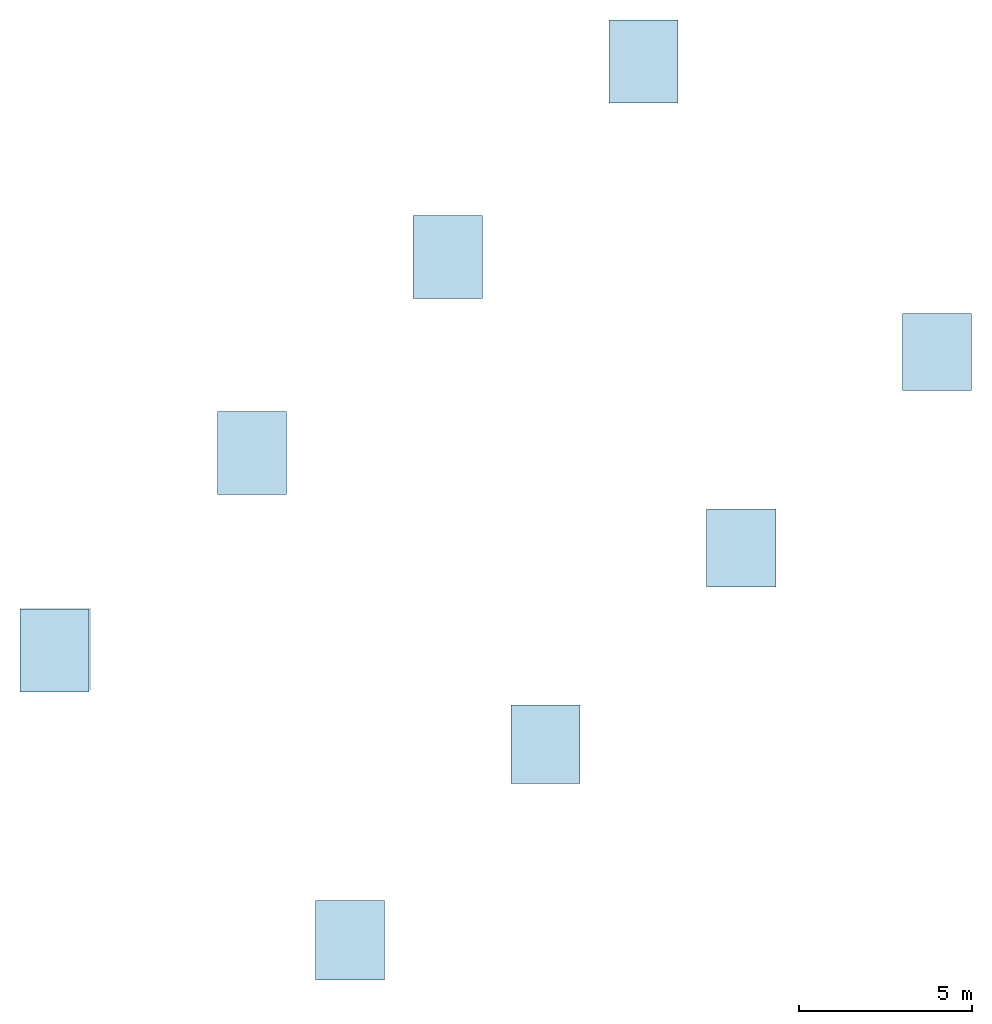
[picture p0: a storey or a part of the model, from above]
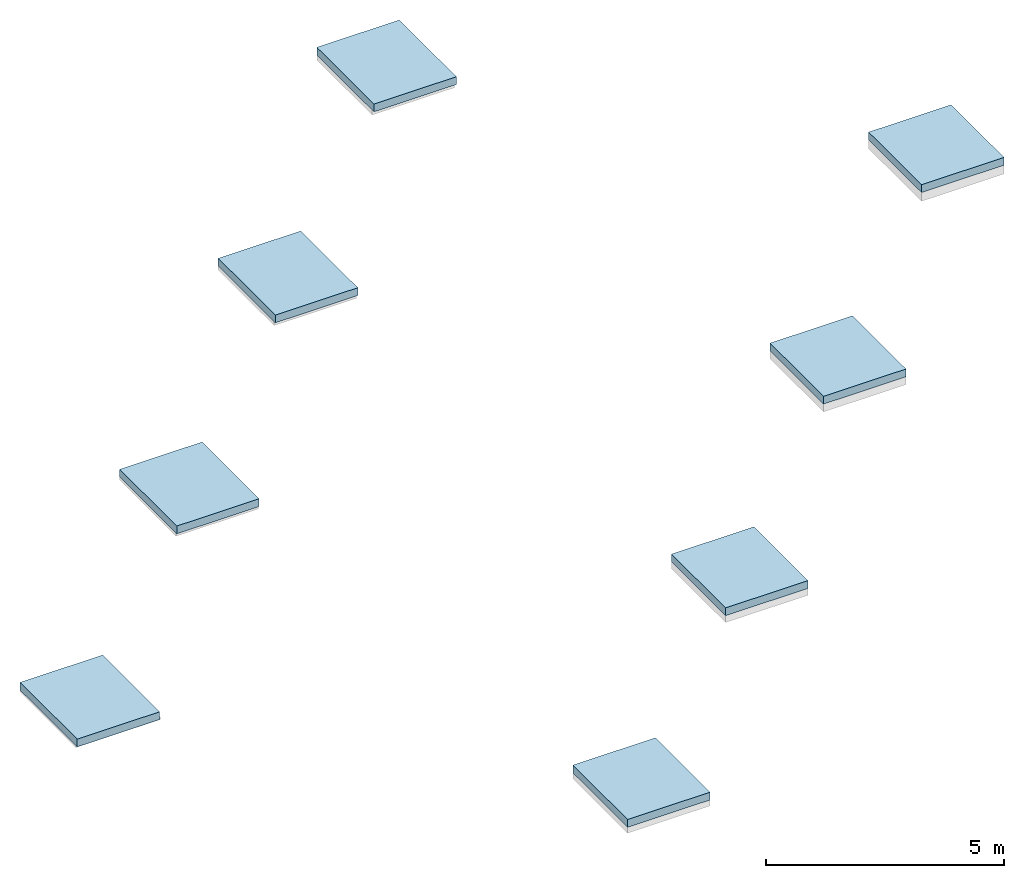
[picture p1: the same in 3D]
Properties of the parts of a building model (IFC2X3), part 1 of 2

# File
Description: ViewDefinition [CoordinationView]
File name: 012345
Time: 2023-01-18T09:48:52
Written by: The EXPRESS Data Manager Version 5.02.0100.07 : 28 Aug 2013
Made in: 21.1.70.21 - Exporter 21.1.70.21 - Alternate UI 21.1.70.21
Comment: STEP Physical File produced by: The EXPRESS Data Manager Version 5.02.0100.07 : 28 Aug 2013 * Module: EDMstepFileFactory/EDMstandAlone * Creation date: Wed Jan 18 09:48:52 2023 * Host: BIM-LT03 * Database: C:\Users\DONNEE~1\AppData\Local\Temp\6dfd9f73-01cb-4fe2-bb7c-203e315a706e\d850b57d-e325-4d6a-91ff-5ca95ef8eb42\ifc * Database version: 5507 * Database creation date: Wed Jan 18 09:48:50 2023 * Schema: IFC2X3 * Model: DataRepository.ifc * Model creation date: Wed Jan 18 09:48:51 2023 * Header model: DataRepository.ifc_HeaderModel * Header model creation date: Wed Jan 18 09:48:51 2023 * EDMuser: sdai-user * EDMgroup: sdai-group * License ID and type: 5605 : Permanent license. Expiry date: * EDMstepFileFactory options: 020000

# IfcProject, 012345
LongName: Cadix Project Naam; Phase: Cadix leeg V2.0

# IfcSite, Default
RefLatitude: 52, 3, 20, 225830; RefLongitude: 5, 6, 28, 692855; RefElevation: 0 mm
Pset_ProductRequirements - Category: Project Information

# IfcBuilding
Pset_BuildingCommon - NumberOfStoreys: 2
Pset_ProductRequirements - Category: Project Information

# IfcBuildingStorey: Level:niveau (2)
Pset_ProductRequirements - Category: Levels
Name | LongName = Pset_AirSideSystemInformation, Name = Pset_ProductRequirements, Name | Elevation (mm)
00 begane grond | 00 begane grond | -2.7707e-11
01 eerste verdieping | 01 eerste verdieping | 1000

# IfcCovering: Compound Ceiling:NLRS_45_CEI_Heraklith Tektalan A2 SmartTec 100x1000x600mm, Compound Ceiling:NLRS_45_CEI_Heraklith Tektalan A2 SmartTec 100x1000x600mm:929619
In: 01 eerste verdieping
Type - PredefinedType: CEILING
Type - Pset_CoveringCommon - Reference: Compound Ceiling:NLRS_45_CEI_Heraklith Tektalan A2 SmartTec 100x1000x600mm; TotalThickness: 100 mm
Type - Pset_ElementShading - Roughness: 304.8 mm
Type - Pset_ManufacturerTypeInformation - Manufacturer: Knauf Insulation B.V.
Type - Pset_ProductRequirements - Category: Ceilings
Type - Pset_QuantityTakeOff - Reference: Compound Ceiling:NLRS_45_CEI_Heraklith Tektalan A2 SmartTec 100x1000x600mm
Type - Pset_Ceiling Schedule LOD200 - Assembly Code: 45.0; Type Image: Raster image: Heraklith Tektalan A2.jpg; Model: Heraklith® | Tektalan A2 SmartTec is een A2 houtwolcementpaneel gecombineerd met een steenwol-plaat.; Manufacturer: Knauf Insulation B.V.; URL: www.heraklith.nl; Description: Tektalan A2 SmartTec - 100mm; phone: +31(0)162-421245; email: customerservice.nl@knaufinsulation.com; product URL: https://heraklith.nl/houtwol-producten/tektalan-a2-smarttec; warmteweerstand: 2,75 (m2.K/W); NLRS_C_Code_Brandklasse: A2-s1,d0; brandweerstand: REI 120/180 mits verwerkt tegen massief beton conform classificatierapport nr 18203 / 18204; geluidsabsorbtie: 1,00; DoP: W4302GPCPR; NLRS_C_content_creator: Knauf Insulation; NLRS_C_content_versie: V1.0
Classification: 45.0 (Uniformat); Material: Heraklith® I Tektalan A2 - Steenwol 90 mm, Heraklith® I Tektalan A2 - Houtwollaag - 1000x600mm 10 mm
Pset_CoveringCommon - Finish: Heraklith® I Tektalan A2 - Houtwollaag - 1000x600mm;
Pset_Ceiling Schedule LOD200 - Type: Compound Ceiling: NLRS_45_CEI_Heraklith Tektalan A2 SmartTec 100x1000x600mm

# IfcCovering: Compound Ceiling:NLRS_45_CEI_Heraklith Tektalan A2 SmartTec 125x1000x600mm, Compound Ceiling:NLRS_45_CEI_Heraklith Tektalan A2 SmartTec 125x1000x600mm:929719
In: 01 eerste verdieping
Type - PredefinedType: CEILING
Type - Pset_CoveringCommon - Reference: Compound Ceiling:NLRS_45_CEI_Heraklith Tektalan A2 SmartTec 125x1000x600mm; TotalThickness: 125 mm
Type - Pset_ElementShading - Roughness: 304.8 mm
Type - Pset_ManufacturerTypeInformation - Manufacturer: Knauf Insulation B.V.
Type - Pset_ProductRequirements - Category: Ceilings
Type - Pset_QuantityTakeOff - Reference: Compound Ceiling:NLRS_45_CEI_Heraklith Tektalan A2 SmartTec 125x1000x600mm
Type - Pset_Ceiling Schedule LOD200 - Assembly Code: 45.0; Type Image: Raster image: Heraklith Tektalan A2.jpg; Model: Heraklith® | Tektalan A2 SmartTec is een A2 houtwolcementpaneel gecombineerd met een steenwol-plaat.; Manufacturer: Knauf Insulation B.V.; URL: www.heraklith.nl; Description: Tektalan A2 SmartTec - 125mm; phone: +31(0)162-421245; email: customerservice.nl@knaufinsulation.com; product URL: https://heraklith.nl/houtwol-producten/tektalan-a2-smarttec; warmteweerstand: 3,50 (m2.K/W); NLRS_C_Code_Brandklasse: A2-s1,d0; brandweerstand: REI 120/180 mits verwerkt tegen massief beton conform classificatierapport nr 18203 / 18204; geluidsabsorbtie: 1,00; DoP: W4302GPCPR; NLRS_C_content_creator: Knauf Insulation; NLRS_C_content_versie: V1.0
Classification: 45.0 (Uniformat); Material: Heraklith® I Tektalan A2 - Steenwol 115 mm, Heraklith® I Tektalan A2 - Houtwollaag - 1000x600mm 10 mm
Pset_CoveringCommon - Finish: Heraklith® I Tektalan A2 - Houtwollaag - 1000x600mm;
Pset_Ceiling Schedule LOD200 - Type: Compound Ceiling: NLRS_45_CEI_Heraklith Tektalan A2 SmartTec 125x1000x600mm

# IfcCovering: Compound Ceiling:NLRS_45_CEI_Heraklith Tektalan A2 SmartTec 150x1000x600mm, Compound Ceiling:NLRS_45_CEI_Heraklith Tektalan A2 SmartTec 150x1000x600mm:929827
In: 01 eerste verdieping
Type - PredefinedType: CEILING
Type - Pset_CoveringCommon - Reference: Compound Ceiling:NLRS_45_CEI_Heraklith Tektalan A2 SmartTec 150x1000x600mm; TotalThickness: 150 mm
Type - Pset_ElementShading - Roughness: 304.8 mm
Type - Pset_ManufacturerTypeInformation - Manufacturer: Knauf Insulation B.V.
Type - Pset_ProductRequirements - Category: Ceilings
Type - Pset_QuantityTakeOff - Reference: Compound Ceiling:NLRS_45_CEI_Heraklith Tektalan A2 SmartTec 150x1000x600mm
Type - Pset_Ceiling Schedule LOD200 - Assembly Code: 45.0; Type Image: Raster image: Heraklith Tektalan A2.jpg; Model: Heraklith® | Tektalan A2 SmartTec is een A2 houtwolcementpaneel gecombineerd met een steenwol-plaat.; Manufacturer: Knauf Insulation B.V.; URL: www.heraklith.nl; Description: Tektalan A2 SmartTec - 150mm; phone: +31(0)162-421245; email: customerservice.nl@knaufinsulation.com; product URL: https://heraklith.nl/houtwol-producten/tektalan-a2-smarttec; warmteweerstand: 4,20 (m2.K/W); NLRS_C_Code_Brandklasse: A2-s1,d0; brandweerstand: REI 120/180 mits verwerkt tegen massief beton conform classificatierapport nr 18203 / 18204; geluidsabsorbtie: 1,00; DoP: W4302GPCPR; NLRS_C_content_creator: Knauf Insulation; NLRS_C_content_versie: V1.0
Classification: 45.0 (Uniformat); Material: Heraklith® I Tektalan A2 - Steenwol 140 mm, Heraklith® I Tektalan A2 - Houtwollaag - 1000x600mm 10 mm
Pset_CoveringCommon - Finish: Heraklith® I Tektalan A2 - Houtwollaag - 1000x600mm;
Pset_Ceiling Schedule LOD200 - Type: Compound Ceiling: NLRS_45_CEI_Heraklith Tektalan A2 SmartTec 150x1000x600mm

# IfcCovering: Compound Ceiling:NLRS_45_CEI_Heraklith Tektalan A2 SmartTec 175x1000x600mm, Compound Ceiling:NLRS_45_CEI_Heraklith Tektalan A2 SmartTec 175x1000x600mm:929851
In: 01 eerste verdieping
Type - PredefinedType: CEILING
Type - Pset_CoveringCommon - Reference: Compound Ceiling:NLRS_45_CEI_Heraklith Tektalan A2 SmartTec 175x1000x600mm; TotalThickness: 175 mm
Type - Pset_ElementShading - Roughness: 304.8 mm
Type - Pset_ManufacturerTypeInformation - Manufacturer: Knauf Insulation B.V.
Type - Pset_ProductRequirements - Category: Ceilings
Type - Pset_QuantityTakeOff - Reference: Compound Ceiling:NLRS_45_CEI_Heraklith Tektalan A2 SmartTec 175x1000x600mm
Type - Pset_Ceiling Schedule LOD200 - Assembly Code: 45.0; Type Image: Raster image: Heraklith Tektalan A2.jpg; Model: Heraklith® | Tektalan A2 SmartTec is een A2 houtwolcementpaneel gecombineerd met een steenwol-plaat.; Manufacturer: Knauf Insulation B.V.; URL: www.heraklith.nl; Description: Tektalan A2 SmartTec - 175mm; phone: +31(0)162-421245; email: customerservice.nl@knaufinsulation.com; product URL: https://heraklith.nl/houtwol-producten/tektalan-a2-smarttec; warmteweerstand: 4,95 (m2.K/W); NLRS_C_Code_Brandklasse: A2-s1,d0; brandweerstand: REI 120/180 mits verwerkt tegen massief beton conform classificatierapport nr 18203 / 18204; geluidsabsorbtie: 1,00; DoP: W4302GPCPR; NLRS_C_content_creator: Knauf Insulation; NLRS_C_content_versie: V1.0
Classification: 45.0 (Uniformat); Material: Heraklith® I Tektalan A2 - Steenwol 165 mm, Heraklith® I Tektalan A2 - Houtwollaag - 1000x600mm 10 mm
Pset_CoveringCommon - Finish: Heraklith® I Tektalan A2 - Houtwollaag - 1000x600mm;
Pset_Ceiling Schedule LOD200 - Type: Compound Ceiling: NLRS_45_CEI_Heraklith Tektalan A2 SmartTec 175x1000x600mm

# IfcCovering: Compound Ceiling:NLRS_45_CEI_Heraklith Tektalan A2 SmartTec 200x1000x600mm, Compound Ceiling:NLRS_45_CEI_Heraklith Tektalan A2 SmartTec 200x1000x600mm:929876
In: 01 eerste verdieping
Type - PredefinedType: CEILING
Type - Pset_CoveringCommon - Reference: Compound Ceiling:NLRS_45_CEI_Heraklith Tektalan A2 SmartTec 200x1000x600mm; TotalThickness: 200 mm
Type - Pset_ElementShading - Roughness: 304.8 mm
Type - Pset_ManufacturerTypeInformation - Manufacturer: Knauf Insulation B.V.
Type - Pset_ProductRequirements - Category: Ceilings
Type - Pset_QuantityTakeOff - Reference: Compound Ceiling:NLRS_45_CEI_Heraklith Tektalan A2 SmartTec 200x1000x600mm
Type - Pset_Ceiling Schedule LOD200 - Assembly Code: 45.0; Type Image: Raster image: Heraklith Tektalan A2.jpg; Model: Heraklith® | Tektalan A2 SmartTec is een A2 houtwolcementpaneel gecombineerd met een steenwol-plaat.; Manufacturer: Knauf Insulation B.V.; URL: www.heraklith.nl; Description: Tektalan A2 SmartTec - 200mm; phone: +31(0)162-421245; email: customerservice.nl@knaufinsulation.com; product URL: https://heraklith.nl/houtwol-producten/tektalan-a2-smarttec; warmteweerstand: 5,70 (m2.K/W); NLRS_C_Code_Brandklasse: A2-s1,d0; brandweerstand: REI 120/180 mits verwerkt tegen massief beton conform classificatierapport nr 18203 / 18204; geluidsabsorbtie: 0,95; DoP: W4302GPCPR; NLRS_C_content_creator: Knauf Insulation; NLRS_C_content_versie: V1.0
Classification: 45.0 (Uniformat); Material: Heraklith® I Tektalan A2 - Steenwol 190 mm, Heraklith® I Tektalan A2 - Houtwollaag - 1000x600mm 10 mm
Pset_CoveringCommon - Finish: Heraklith® I Tektalan A2 - Houtwollaag - 1000x600mm;
Pset_Ceiling Schedule LOD200 - Type: Compound Ceiling: NLRS_45_CEI_Heraklith Tektalan A2 SmartTec 200x1000x600mm

# IfcCovering: Compound Ceiling:NLRS_45_CEI_Heraklith Tektalan A2 SmartTec 225x1000x600mm, Compound Ceiling:NLRS_45_CEI_Heraklith Tektalan A2 SmartTec 225x1000x600mm:929901
In: 01 eerste verdieping
Type - PredefinedType: CEILING
Type - Pset_CoveringCommon - Reference: Compound Ceiling:NLRS_45_CEI_Heraklith Tektalan A2 SmartTec 225x1000x600mm; TotalThickness: 225 mm
Type - Pset_ElementShading - Roughness: 304.8 mm
Type - Pset_ManufacturerTypeInformation - Manufacturer: Knauf Insulation B.V.
Type - Pset_ProductRequirements - Category: Ceilings
Type - Pset_QuantityTakeOff - Reference: Compound Ceiling:NLRS_45_CEI_Heraklith Tektalan A2 SmartTec 225x1000x600mm
Type - Pset_Ceiling Schedule LOD200 - Assembly Code: 45.0; Type Image: Raster image: Heraklith Tektalan A2.jpg; Model: Heraklith® | Tektalan A2 SmartTec is een A2 houtwolcementpaneel gecombineerd met een steenwol-plaat.; Manufacturer: Knauf Insulation B.V.; URL: www.heraklith.nl; Description: Tektalan A2 SmartTec - 225mm; phone: +31(0)162-421245; email: customerservice.nl@knaufinsulation.com; product URL: https://heraklith.nl/houtwol-producten/tektalan-a2-smarttec; warmteweerstand: 6,40 (m2.K/W); NLRS_C_Code_Brandklasse: A2-s1,d0; brandweerstand: REI 120/180 mits verwerkt tegen massief beton conform classificatierapport nr 18203 / 18204; geluidsabsorbtie: 0,95; DoP: W4302GPCPR; NLRS_C_content_creator: Knauf Insulation; NLRS_C_content_versie: V1.0
Classification: 45.0 (Uniformat); Material: Heraklith® I Tektalan A2 - Steenwol 215 mm, Heraklith® I Tektalan A2 - Houtwollaag - 1000x600mm 10 mm
Pset_CoveringCommon - Finish: Heraklith® I Tektalan A2 - Houtwollaag - 1000x600mm;
Pset_Ceiling Schedule LOD200 - Type: Compound Ceiling: NLRS_45_CEI_Heraklith Tektalan A2 SmartTec 225x1000x600mm

# IfcCovering: Compound Ceiling:NLRS_45_CEI_Heraklith Tektalan A2 SmartTec 50x1000x600mm, Compound Ceiling:NLRS_45_CEI_Heraklith Tektalan A2 SmartTec 50x1000x600mm:905808
In: 01 eerste verdieping
Type - PredefinedType: CEILING
Type - Pset_CoveringCommon - Reference: Compound Ceiling:NLRS_45_CEI_Heraklith Tektalan A2 SmartTec 50x1000x600mm; TotalThickness: 50 mm
Type - Pset_ElementShading - Roughness: 304.8 mm
Type - Pset_ManufacturerTypeInformation - Manufacturer: Knauf Insulation B.V.
Type - Pset_ProductRequirements - Category: Ceilings
Type - Pset_QuantityTakeOff - Reference: Compound Ceiling:NLRS_45_CEI_Heraklith Tektalan A2 SmartTec 50x1000x600mm
Type - Pset_Ceiling Schedule LOD200 - Assembly Code: 45.0; Type Image: Raster image: Heraklith Tektalan A2.jpg; Model: Heraklith® | Tektalan A2 SmartTec is een A2 houtwolcementpaneel gecombineerd met een steenwol-plaat.; Manufacturer: Knauf Insulation B.V.; URL: www.heraklith.nl; Description: Tektalan A2 SmartTec - 50mm; phone: +31(0)162-421245; email: customerservice.nl@knaufinsulation.com; product URL: https://heraklith.nl/houtwol-producten/tektalan-a2-smarttec; warmteweerstand: 1,25 (m2.K/W); NLRS_C_Code_Brandklasse: A2-s1,d0; brandweerstand: REI 120/180 mits verwerkt tegen massief beton conform classificatierapport nr 18203 / 18204; geluidsabsorbtie: 0,95; DoP: W4302GPCPR; NLRS_C_content_creator: Knauf Insulation; NLRS_C_content_versie: V1.0
Classification: 45.0 (Uniformat); Material: Heraklith® I Tektalan A2 - Steenwol 40 mm, Heraklith® I Tektalan A2 - Houtwollaag - 1000x600mm 10 mm
Pset_CoveringCommon - Finish: Heraklith® I Tektalan A2 - Houtwollaag - 1000x600mm;
Pset_Ceiling Schedule LOD200 - Type: Compound Ceiling: NLRS_45_CEI_Heraklith Tektalan A2 SmartTec 50x1000x600mm

# IfcCovering: Compound Ceiling:NLRS_45_CEI_Heraklith Tektalan A2 SmartTec 75x1000x600mm, Compound Ceiling:NLRS_45_CEI_Heraklith Tektalan A2 SmartTec 75x1000x600mm:929506
In: 01 eerste verdieping
Type - PredefinedType: CEILING
Type - Pset_CoveringCommon - Reference: Compound Ceiling:NLRS_45_CEI_Heraklith Tektalan A2 SmartTec 75x1000x600mm; TotalThickness: 75 mm
Type - Pset_ElementShading - Roughness: 304.8 mm
Type - Pset_ManufacturerTypeInformation - Manufacturer: Knauf Insulation B.V.
Type - Pset_ProductRequirements - Category: Ceilings
Type - Pset_QuantityTakeOff - Reference: Compound Ceiling:NLRS_45_CEI_Heraklith Tektalan A2 SmartTec 75x1000x600mm
Type - Pset_Ceiling Schedule LOD200 - Assembly Code: 45.0; Type Image: Raster image: Heraklith Tektalan A2.jpg; Model: Heraklith® | Tektalan A2 SmartTec is een A2 houtwolcementpaneel gecombineerd met een steenwol-plaat.; Manufacturer: Knauf Insulation B.V.; URL: www.heraklith.nl; Description: Tektalan A2 SmartTec - 75mm; phone: +31(0)162-421245; email: customerservice.nl@knaufinsulation.com; product URL: https://heraklith.nl/houtwol-producten/tektalan-a2-smarttec; warmteweerstand: 2,00 (m2.K/W); NLRS_C_Code_Brandklasse: A2-s1,d0; brandweerstand: REI 120/180 mits verwerkt tegen massief beton conform classificatierapport nr 18203 / 18204; geluidsabsorbtie: 0,95; DoP: W4302GPCPR; NLRS_C_content_creator: Knauf Insulation; NLRS_C_content_versie: V1.0
Classification: 45.0 (Uniformat); Material: Heraklith® I Tektalan A2 - Steenwol 65 mm, Heraklith® I Tektalan A2 - Houtwollaag - 1000x600mm 10 mm
Pset_CoveringCommon - Finish: Heraklith® I Tektalan A2 - Houtwollaag - 1000x600mm;
Pset_Ceiling Schedule LOD200 - Type: Compound Ceiling: NLRS_45_CEI_Heraklith Tektalan A2 SmartTec 75x1000x600mm

# IfcSlab: Floor:Generic 200mm (16)
Type - PredefinedType: FLOOR; Material: Concrete, Precast Panels 200 mm
Type - Pset_ElementShading - Roughness: 914.4 mm
Type - Pset_ProductRequirements - Category: Floors
Type - Pset_QuantityTakeOff - Reference: Floor:Generic 200mm
Type - Pset_ReinforcementBarPitchOfSlab - Reference: Floor:Generic 200mm
Type - Pset_SlabCommon - IsExternal: no; Reference: Floor:Generic 200mm; ThermalTransmittance: 5.23 kg/K/s3
Pset_QuantityTakeOff - sets with these values: 2
Pset_SlabCommon - LoadBearing: no; PitchAngle: 0 deg
Name (Floor:Generic 200mm:...) | In
934649 | 01 eerste verdieping
934796 | 01 eerste verdieping
934810 | 01 eerste verdieping
934824 | 01 eerste verdieping
934838 | 01 eerste verdieping
934854 | 01 eerste verdieping
934868 | 01 eerste verdieping
934884 | 01 eerste verdieping
936492 | 00 begane grond
936538 | 00 begane grond
936553 | 00 begane grond
936570 | 00 begane grond
936585 | 00 begane grond
936600 | 00 begane grond
936619 | 00 begane grond
936634 | 00 begane grond

# IfcSlab: Floor:NLRS_23_FL_Heraklith Tektalan A2 SmartTec 100x1000x600mm, Floor:NLRS_23_FL_Heraklith Tektalan A2 SmartTec 100x1000x600mm:929624
In: 00 begane grond
Type - PredefinedType: FLOOR; Material: Heraklith® I Tektalan A2 - Steenwol 90 mm, Heraklith® I Tektalan A2 - Houtwollaag - 1000x600mm 10 mm
Type - Pset_ElementShading - Roughness: 304.8 mm
Type - Pset_ManufacturerTypeInformation - Manufacturer: Knauf Insulation B.V.
Type - Pset_ProductRequirements - Category: Floors
Type - Pset_QuantityTakeOff - Reference: Floor:NLRS_23_FL_Heraklith Tektalan A2 SmartTec 100x1000x600mm
Type - Pset_ReinforcementBarPitchOfSlab - Description: Tektalan A2 SmartTec - 100mm; Reference: Floor:NLRS_23_FL_Heraklith Tektalan A2 SmartTec 100x1000x600mm
Type - Pset_SlabCommon - IsExternal: no; Reference: Floor:NLRS_23_FL_Heraklith Tektalan A2 SmartTec 100x1000x600mm; ThermalTransmittance: 0.361702 kg/K/s3
Type - Pset_Floor Schedule LOD200 - Assembly Code: 23.0; Type Image: Raster image: Heraklith Tektalan A2.jpg; Model: Heraklith® | Tektalan A2 SmartTec is een A2 houtwolcementpaneel gecombineerd met een steenwol-plaat.; Manufacturer: Knauf Insulation B.V.; URL: www.heraklith.nl; Description: Tektalan A2 SmartTec - 100mm; phone: +31(0)162-421245; email: customerservice.nl@knaufinsulation.com; product URL: https://heraklith.nl/houtwol-producten/tektalan-a2-smarttec; warmteweerstand: 2,75 (m2.K/W); NLRS_C_Code_Brandklasse: A2-s1,d0; brandweerstand: REI 120/180 mits verwerkt tegen massief beton conform classificatierapport nr 18203 / 18204; geluidsabsorbtie: 1,00; DoP: W4302GPCPR; NLRS_C_content_creator: Knauf Insulation; NLRS_C_content_versie: V1.0
Classification: 23.0 (Uniformat)
Pset_SlabCommon - IsExternal: yes; LoadBearing: no; PitchAngle: 0 deg
Pset_Floor Schedule LOD200 - Type: Floor: NLRS_23_FL_Heraklith Tektalan A2 SmartTec 100x1000x600mm

# IfcSlab: Floor:NLRS_23_FL_Heraklith Tektalan A2 SmartTec 125x1000x600mm, Floor:NLRS_23_FL_Heraklith Tektalan A2 SmartTec 125x1000x600mm:929724
In: 00 begane grond
Type - PredefinedType: FLOOR; Material: Heraklith® I Tektalan A2 - Steenwol 115 mm, Heraklith® I Tektalan A2 - Houtwollaag - 1000x600mm 10 mm
Type - Pset_ElementShading - Roughness: 304.8 mm
Type - Pset_ManufacturerTypeInformation - Manufacturer: Knauf Insulation B.V.
Type - Pset_ProductRequirements - Category: Floors
Type - Pset_QuantityTakeOff - Reference: Floor:NLRS_23_FL_Heraklith Tektalan A2 SmartTec 125x1000x600mm
Type - Pset_ReinforcementBarPitchOfSlab - Description: Tektalan A2 SmartTec - 125mm; Reference: Floor:NLRS_23_FL_Heraklith Tektalan A2 SmartTec 125x1000x600mm
Type - Pset_SlabCommon - IsExternal: no; Reference: Floor:NLRS_23_FL_Heraklith Tektalan A2 SmartTec 125x1000x600mm; ThermalTransmittance: 0.285714 kg/K/s3
Type - Pset_Floor Schedule LOD200 - Assembly Code: 23.0; Type Image: Raster image: Heraklith Tektalan A2.jpg; Model: Heraklith® | Tektalan A2 SmartTec is een A2 houtwolcementpaneel gecombineerd met een steenwol-plaat.; Manufacturer: Knauf Insulation B.V.; URL: www.heraklith.nl; Description: Tektalan A2 SmartTec - 125mm; phone: +31(0)162-421245; email: customerservice.nl@knaufinsulation.com; product URL: https://heraklith.nl/houtwol-producten/tektalan-a2-smarttec; warmteweerstand: 3,50 (m2.K/W); NLRS_C_Code_Brandklasse: A2-s1,d0; brandweerstand: REI 120/180 mits verwerkt tegen massief beton conform classificatierapport nr 18203 / 18204; geluidsabsorbtie: 1,00; DoP: W4302GPCPR; NLRS_C_content_creator: Knauf Insulation; NLRS_C_content_versie: V1.0
Classification: 23.0 (Uniformat)
Pset_SlabCommon - IsExternal: yes; LoadBearing: no; PitchAngle: 0 deg
Pset_Floor Schedule LOD200 - Type: Floor: NLRS_23_FL_Heraklith Tektalan A2 SmartTec 125x1000x600mm

# IfcSlab: Floor:NLRS_23_FL_Heraklith Tektalan A2 SmartTec 150x1000x600mm, Floor:NLRS_23_FL_Heraklith Tektalan A2 SmartTec 150x1000x600mm:929832
In: 00 begane grond
Type - PredefinedType: FLOOR; Material: Heraklith® I Tektalan A2 - Steenwol 140 mm, Heraklith® I Tektalan A2 - Houtwollaag - 1000x600mm 10 mm
Type - Pset_ElementShading - Roughness: 304.8 mm
Type - Pset_ManufacturerTypeInformation - Manufacturer: Knauf Insulation B.V.
Type - Pset_ProductRequirements - Category: Floors
Type - Pset_QuantityTakeOff - Reference: Floor:NLRS_23_FL_Heraklith Tektalan A2 SmartTec 150x1000x600mm
Type - Pset_ReinforcementBarPitchOfSlab - Description: Tektalan A2 SmartTec - 150mm; Reference: Floor:NLRS_23_FL_Heraklith Tektalan A2 SmartTec 150x1000x600mm
Type - Pset_SlabCommon - IsExternal: no; Reference: Floor:NLRS_23_FL_Heraklith Tektalan A2 SmartTec 150x1000x600mm; ThermalTransmittance: 0.236111 kg/K/s3
Type - Pset_Floor Schedule LOD200 - Assembly Code: 23.0; Type Image: Raster image: Heraklith Tektalan A2.jpg; Model: Heraklith® | Tektalan A2 SmartTec is een A2 houtwolcementpaneel gecombineerd met een steenwol-plaat.; Manufacturer: Knauf Insulation B.V.; URL: www.heraklith.nl; Description: Tektalan A2 SmartTec - 150mm; phone: +31(0)162-421245; email: customerservice.nl@knaufinsulation.com; product URL: https://heraklith.nl/houtwol-producten/tektalan-a2-smarttec; warmteweerstand: 4,20 (m2.K/W); NLRS_C_Code_Brandklasse: A2-s1,d0; brandweerstand: REI 120/180 mits verwerkt tegen massief beton conform classificatierapport nr 18203 / 18204; geluidsabsorbtie: 1,00; DoP: W4302GPCPR; NLRS_C_content_creator: Knauf Insulation; NLRS_C_content_versie: V1.0
Classification: 23.0 (Uniformat)
Pset_SlabCommon - IsExternal: yes; LoadBearing: no; PitchAngle: 0 deg
Pset_Floor Schedule LOD200 - Type: Floor: NLRS_23_FL_Heraklith Tektalan A2 SmartTec 150x1000x600mm

# IfcSlab: Floor:NLRS_23_FL_Heraklith Tektalan A2 SmartTec 175x1000x600mm, Floor:NLRS_23_FL_Heraklith Tektalan A2 SmartTec 175x1000x600mm:929856
In: 00 begane grond
Type - PredefinedType: FLOOR; Material: Heraklith® I Tektalan A2 - Steenwol 165 mm, Heraklith® I Tektalan A2 - Houtwollaag - 1000x600mm 10 mm
Type - Pset_ElementShading - Roughness: 304.8 mm
Type - Pset_ManufacturerTypeInformation - Manufacturer: Knauf Insulation B.V.
Type - Pset_ProductRequirements - Category: Floors
Type - Pset_QuantityTakeOff - Reference: Floor:NLRS_23_FL_Heraklith Tektalan A2 SmartTec 175x1000x600mm
Type - Pset_ReinforcementBarPitchOfSlab - Description: Tektalan A2 SmartTec - 175mm; Reference: Floor:NLRS_23_FL_Heraklith Tektalan A2 SmartTec 175x1000x600mm
Type - Pset_SlabCommon - IsExternal: no; Reference: Floor:NLRS_23_FL_Heraklith Tektalan A2 SmartTec 175x1000x600mm; ThermalTransmittance: 0.201183 kg/K/s3
Type - Pset_Floor Schedule LOD200 - Assembly Code: 23.0; Type Image: Raster image: Heraklith Tektalan A2.jpg; Model: Heraklith® | Tektalan A2 SmartTec is een A2 houtwolcementpaneel gecombineerd met een steenwol-plaat.; Manufacturer: Knauf Insulation B.V.; URL: www.heraklith.nl; Description: Tektalan A2 SmartTec - 175mm; phone: +31(0)162-421245; email: customerservice.nl@knaufinsulation.com; product URL: https://heraklith.nl/houtwol-producten/tektalan-a2-smarttec; warmteweerstand: 4,95 (m2.K/W); NLRS_C_Code_Brandklasse: A2-s1,d0; brandweerstand: REI 120/180 mits verwerkt tegen massief beton conform classificatierapport nr 18203 / 18204; geluidsabsorbtie: 1,00; DoP: W4302GPCPR; NLRS_C_content_creator: Knauf Insulation; NLRS_C_content_versie: V1.0
Classification: 23.0 (Uniformat)
Pset_SlabCommon - IsExternal: yes; LoadBearing: no; PitchAngle: 0 deg
Pset_Floor Schedule LOD200 - Type: Floor: NLRS_23_FL_Heraklith Tektalan A2 SmartTec 175x1000x600mm

# IfcSlab: Floor:NLRS_23_FL_Heraklith Tektalan A2 SmartTec 200x1000x600mm, Floor:NLRS_23_FL_Heraklith Tektalan A2 SmartTec 200x1000x600mm:929881
In: 00 begane grond
Type - PredefinedType: FLOOR; Material: Heraklith® I Tektalan A2 - Steenwol 190 mm, Heraklith® I Tektalan A2 - Houtwollaag - 1000x600mm 10 mm
Type - Pset_ElementShading - Roughness: 304.8 mm
Type - Pset_ManufacturerTypeInformation - Manufacturer: Knauf Insulation B.V.
Type - Pset_ProductRequirements - Category: Floors
Type - Pset_QuantityTakeOff - Reference: Floor:NLRS_23_FL_Heraklith Tektalan A2 SmartTec 200x1000x600mm
Type - Pset_ReinforcementBarPitchOfSlab - Description: Tektalan A2 SmartTec - 200mm; Reference: Floor:NLRS_23_FL_Heraklith Tektalan A2 SmartTec 200x1000x600mm
Type - Pset_SlabCommon - IsExternal: no; Reference: Floor:NLRS_23_FL_Heraklith Tektalan A2 SmartTec 200x1000x600mm; ThermalTransmittance: 0.175258 kg/K/s3
Type - Pset_Floor Schedule LOD200 - Assembly Code: 23.0; Type Image: Raster image: Heraklith Tektalan A2.jpg; Model: Heraklith® | Tektalan A2 SmartTec is een A2 houtwolcementpaneel gecombineerd met een steenwol-plaat.; Manufacturer: Knauf Insulation B.V.; URL: www.heraklith.nl; Description: Tektalan A2 SmartTec - 200mm; phone: +31(0)162-421245; email: customerservice.nl@knaufinsulation.com; product URL: https://heraklith.nl/houtwol-producten/tektalan-a2-smarttec; warmteweerstand: 5,70 (m2.K/W); NLRS_C_Code_Brandklasse: A2-s1,d0; brandweerstand: REI 120/180 mits verwerkt tegen massief beton conform classificatierapport nr 18203 / 18204; geluidsabsorbtie: 0,95; DoP: W4302GPCPR; NLRS_C_content_creator: Knauf Insulation; NLRS_C_content_versie: V1.0
Classification: 23.0 (Uniformat)
Pset_SlabCommon - IsExternal: yes; LoadBearing: no; PitchAngle: 0 deg
Pset_Floor Schedule LOD200 - Type: Floor: NLRS_23_FL_Heraklith Tektalan A2 SmartTec 200x1000x600mm

# IfcSlab: Floor:NLRS_23_FL_Heraklith Tektalan A2 SmartTec 225x1000x600mm, Floor:NLRS_23_FL_Heraklith Tektalan A2 SmartTec 225x1000x600mm:929906
In: 00 begane grond
Type - PredefinedType: FLOOR; Material: Heraklith® I Tektalan A2 - Steenwol 215 mm, Heraklith® I Tektalan A2 - Houtwollaag - 1000x600mm 10 mm
Type - Pset_ElementShading - Roughness: 304.8 mm
Type - Pset_ManufacturerTypeInformation - Manufacturer: Knauf Insulation B.V.
Type - Pset_ProductRequirements - Category: Floors
Type - Pset_QuantityTakeOff - Reference: Floor:NLRS_23_FL_Heraklith Tektalan A2 SmartTec 225x1000x600mm
Type - Pset_ReinforcementBarPitchOfSlab - Description: Tektalan A2 SmartTec - 225mm; Reference: Floor:NLRS_23_FL_Heraklith Tektalan A2 SmartTec 225x1000x600mm
Type - Pset_SlabCommon - IsExternal: no; Reference: Floor:NLRS_23_FL_Heraklith Tektalan A2 SmartTec 225x1000x600mm; ThermalTransmittance: 0.155251 kg/K/s3
Type - Pset_Floor Schedule LOD200 - Assembly Code: 23.0; Type Image: Raster image: Heraklith Tektalan A2.jpg; Model: Heraklith® | Tektalan A2 SmartTec is een A2 houtwolcementpaneel gecombineerd met een steenwol-plaat.; Manufacturer: Knauf Insulation B.V.; URL: www.heraklith.nl; Description: Tektalan A2 SmartTec - 225mm; phone: +31(0)162-421245; email: customerservice.nl@knaufinsulation.com; product URL: https://heraklith.nl/houtwol-producten/tektalan-a2-smarttec; warmteweerstand: 6,40 (m2.K/W); NLRS_C_Code_Brandklasse: A2-s1,d0; brandweerstand: REI 120/180 mits verwerkt tegen massief beton conform classificatierapport nr 18203 / 18204; geluidsabsorbtie: 0,95; DoP: W4302GPCPR; NLRS_C_content_creator: Knauf Insulation; NLRS_C_content_versie: V1.0
Classification: 23.0 (Uniformat)
Pset_SlabCommon - IsExternal: yes; LoadBearing: no; PitchAngle: 0 deg
Pset_Floor Schedule LOD200 - Type: Floor: NLRS_23_FL_Heraklith Tektalan A2 SmartTec 225x1000x600mm

# IfcSlab: Floor:NLRS_23_FL_Heraklith Tektalan A2 SmartTec 50x1000x600mm, Floor:NLRS_23_FL_Heraklith Tektalan A2 SmartTec 50x1000x600mm:905817
In: 00 begane grond
Type - PredefinedType: FLOOR; Material: Heraklith® I Tektalan A2 - Steenwol 40 mm, Heraklith® I Tektalan A2 - Houtwollaag - 1000x600mm 10 mm
Type - Pset_ElementShading - Roughness: 304.8 mm
Type - Pset_ManufacturerTypeInformation - Manufacturer: Knauf Insulation B.V.
Type - Pset_ProductRequirements - Category: Floors
Type - Pset_QuantityTakeOff - Reference: Floor:NLRS_23_FL_Heraklith Tektalan A2 SmartTec 50x1000x600mm
Type - Pset_ReinforcementBarPitchOfSlab - Description: Tektalan A2 SmartTec - 50mm; Reference: Floor:NLRS_23_FL_Heraklith Tektalan A2 SmartTec 50x1000x600mm
Type - Pset_SlabCommon - IsExternal: no; Reference: Floor:NLRS_23_FL_Heraklith Tektalan A2 SmartTec 50x1000x600mm; ThermalTransmittance: 0.772727 kg/K/s3
Type - Pset_Floor Schedule LOD200 - Assembly Code: 23.0; Type Image: Raster image: Heraklith Tektalan A2.jpg; Model: Heraklith® | Tektalan A2 SmartTec is een A2 houtwolcementpaneel gecombineerd met een steenwol-plaat.; Manufacturer: Knauf Insulation B.V.; URL: www.heraklith.nl; Description: Tektalan A2 SmartTec - 50mm; phone: +31(0)162-421245; email: customerservice.nl@knaufinsulation.com; product URL: https://heraklith.nl/houtwol-producten/tektalan-a2-smarttec; warmteweerstand: 1,25 (m2.K/W); NLRS_C_Code_Brandklasse: A2-s1,d0; brandweerstand: REI 120/180 mits verwerkt tegen massief beton conform classificatierapport nr 18203 / 18204; geluidsabsorbtie: 0,95; DoP: W4302GPCPR; NLRS_C_content_creator: Knauf Insulation; NLRS_C_content_versie: V1.0
Classification: 23.0 (Uniformat)
Pset_SlabCommon - IsExternal: yes; LoadBearing: no; PitchAngle: 0 deg
Pset_Floor Schedule LOD200 - Type: Floor: NLRS_23_FL_Heraklith Tektalan A2 SmartTec 50x1000x600mm

# IfcSlab: Floor:NLRS_23_FL_Heraklith Tektalan A2 SmartTec 75x1000x600mm, Floor:NLRS_23_FL_Heraklith Tektalan A2 SmartTec 75x1000x600mm:929511
In: 00 begane grond
Type - PredefinedType: FLOOR; Material: Heraklith® I Tektalan A2 - Steenwol 65 mm, Heraklith® I Tektalan A2 - Houtwollaag - 1000x600mm 10 mm
Type - Pset_ElementShading - Roughness: 304.8 mm
Type - Pset_ManufacturerTypeInformation - Manufacturer: Knauf Insulation B.V.
Type - Pset_ProductRequirements - Category: Floors
Type - Pset_QuantityTakeOff - Reference: Floor:NLRS_23_FL_Heraklith Tektalan A2 SmartTec 75x1000x600mm
Type - Pset_ReinforcementBarPitchOfSlab - Description: Tektalan A2 SmartTec - 75mm; Reference: Floor:NLRS_23_FL_Heraklith Tektalan A2 SmartTec 75x1000x600mm
Type - Pset_SlabCommon - IsExternal: no; Reference: Floor:NLRS_23_FL_Heraklith Tektalan A2 SmartTec 75x1000x600mm; ThermalTransmittance: 0.492754 kg/K/s3
Type - Pset_Floor Schedule LOD200 - Assembly Code: 23.0; Type Image: Raster image: Heraklith Tektalan A2.jpg; Model: Heraklith® | Tektalan A2 SmartTec is een A2 houtwolcementpaneel gecombineerd met een steenwol-plaat.; Manufacturer: Knauf Insulation B.V.; URL: www.heraklith.nl; Description: Tektalan A2 SmartTec - 75mm; phone: +31(0)162-421245; email: customerservice.nl@knaufinsulation.com; product URL: https://heraklith.nl/houtwol-producten/tektalan-a2-smarttec; warmteweerstand: 2,00 (m2.K/W); NLRS_C_Code_Brandklasse: A2-s1,d0; brandweerstand: REI 120/180 mits verwerkt tegen massief beton conform classificatierapport nr 18203 / 18204; geluidsabsorbtie: 0,95; DoP: W4302GPCPR; NLRS_C_content_creator: Knauf Insulation; NLRS_C_content_versie: V1.0
Classification: 23.0 (Uniformat)
Pset_SlabCommon - IsExternal: yes; LoadBearing: no; PitchAngle: 0 deg
Pset_Floor Schedule LOD200 - Type: Floor: NLRS_23_FL_Heraklith Tektalan A2 SmartTec 75x1000x600mm

# IfcWallStandardCase: Basic Wall:Generic_100mm (16)
In: 00 begane grond
Type - PredefinedType: STANDARD; Material: Concrete, Precast Panels 100 mm
Type - Pset_ElementShading - Roughness: 914.4 mm
Type - Pset_ProductRequirements - Category: Walls
Type - Pset_QuantityTakeOff - Reference: Basic Wall:Generic_100mm
Type - Pset_ReinforcementBarPitchOfWall - Reference: Basic Wall:Generic_100mm
Type - Pset_WallCommon - IsExternal: no; Reference: Basic Wall:Generic_100mm; ThermalTransmittance: 10.46 kg/K/s3
Pset_QuantityTakeOff - sets with these values: 2
Pset_WallCommon - IsExternal: yes; ExtendToStructure: no; LoadBearing: no
Name (Basic Wall:Generic_100mm:...)
936009
936086
936282
936342
936421
936422
936431
936432
936441
936442
936453
936454
936465
936466
936477
936478

# IfcWallStandardCase: Basic Wall:NLRS_41_WA_Heraklith Tektalan A2 SmartTec 100x1000x600mm, Basic Wall:NLRS_41_WA_Heraklith Tektalan A2 SmartTec 100x1000x600mm:929620
In: 00 begane grond
Type - PredefinedType: STANDARD; Material: Heraklith® I Tektalan A2 - Steenwol 90 mm, Heraklith® I Tektalan A2 - Houtwollaag - 1000x600mm 10 mm
Type - Pset_ElementShading - Roughness: 304.8 mm
Type - Pset_ManufacturerTypeInformation - Manufacturer: Knauf Insulation B.V.
Type - Pset_ProductRequirements - Category: Walls
Type - Pset_QuantityTakeOff - Reference: Basic Wall:NLRS_41_WA_Heraklith Tektalan A2 SmartTec 100x1000x600mm
Type - Pset_ReinforcementBarPitchOfWall - Description: Tektalan A2 SmartTec - 100mm; Reference: Basic Wall:NLRS_41_WA_Heraklith Tektalan A2 SmartTec 100x1000x600mm
Type - Pset_WallCommon - IsExternal: no; Reference: Basic Wall:NLRS_41_WA_Heraklith Tektalan A2 SmartTec 100x1000x600mm; ThermalTransmittance: 0.361702 kg/K/s3
Type - Pset_Wall Schedule LOD200 - Assembly Code: 41.10; Type Image: Raster image: Heraklith Tektalan A2.jpg; Model: Heraklith® | Tektalan A2 SmartTec is een A2 houtwolcementpaneel gecombineerd met een steenwol-plaat.; Manufacturer: Knauf Insulation B.V.; URL: www.heraklith.nl; Description: Tektalan A2 SmartTec - 100mm; phone: +31(0)162-421245; email: customerservice.nl@knaufinsulation.com; product URL: https://heraklith.nl/houtwol-producten/tektalan-a2-smarttec; warmteweerstand: 2,75 (m2.K/W); NLRS_C_Code_Brandklasse: A2-s1,d0; brandweerstand: REI 120/180 mits verwerkt tegen massief beton conform classificatierapport nr 18203 / 18204; geluidsabsorbtie: 1,00; DoP: W4302GPCPR; NLRS_C_content_creator: Knauf Insulation; NLRS_C_content_versie: V1.0
Classification: 41.10 (Uniformat)
Pset_WallCommon - IsExternal: yes; ExtendToStructure: no; LoadBearing: no
Pset_Wall Schedule LOD200 - Type: Basic Wall: NLRS_41_WA_Heraklith Tektalan A2 SmartTec 100x1000x600mm

# IfcWallStandardCase: Basic Wall:NLRS_41_WA_Heraklith Tektalan A2 SmartTec 125x1000x600mm, Basic Wall:NLRS_41_WA_Heraklith Tektalan A2 SmartTec 125x1000x600mm:929720
In: 00 begane grond
Type - PredefinedType: STANDARD; Material: Heraklith® I Tektalan A2 - Steenwol 115 mm, Heraklith® I Tektalan A2 - Houtwollaag - 1000x600mm 10 mm
Type - Pset_ElementShading - Roughness: 304.8 mm
Type - Pset_ManufacturerTypeInformation - Manufacturer: Knauf Insulation B.V.
Type - Pset_ProductRequirements - Category: Walls
Type - Pset_QuantityTakeOff - Reference: Basic Wall:NLRS_41_WA_Heraklith Tektalan A2 SmartTec 125x1000x600mm
Type - Pset_ReinforcementBarPitchOfWall - Description: Tektalan A2 SmartTec - 125mm; Reference: Basic Wall:NLRS_41_WA_Heraklith Tektalan A2 SmartTec 125x1000x600mm
Type - Pset_WallCommon - IsExternal: no; Reference: Basic Wall:NLRS_41_WA_Heraklith Tektalan A2 SmartTec 125x1000x600mm; ThermalTransmittance: 0.285714 kg/K/s3
Type - Pset_Wall Schedule LOD200 - Assembly Code: 41.10; Type Image: Raster image: Heraklith Tektalan A2.jpg; Model: Heraklith® | Tektalan A2 SmartTec is een A2 houtwolcementpaneel gecombineerd met een steenwol-plaat.; Manufacturer: Knauf Insulation B.V.; URL: www.heraklith.nl; Description: Tektalan A2 SmartTec - 125mm; phone: +31(0)162-421245; email: customerservice.nl@knaufinsulation.com; product URL: https://heraklith.nl/houtwol-producten/tektalan-a2-smarttec; warmteweerstand: 3,50 (m2.K/W); NLRS_C_Code_Brandklasse: A2-s1,d0; brandweerstand: REI 120/180 mits verwerkt tegen massief beton conform classificatierapport nr 18203 / 18204; geluidsabsorbtie: 1,00; DoP: W4302GPCPR; NLRS_C_content_creator: Knauf Insulation; NLRS_C_content_versie: V1.0
Classification: 41.10 (Uniformat)
Pset_WallCommon - IsExternal: yes; ExtendToStructure: no; LoadBearing: no
Pset_Wall Schedule LOD200 - Type: Basic Wall: NLRS_41_WA_Heraklith Tektalan A2 SmartTec 125x1000x600mm

# IfcWallStandardCase: Basic Wall:NLRS_41_WA_Heraklith Tektalan A2 SmartTec 150x1000x600mm, Basic Wall:NLRS_41_WA_Heraklith Tektalan A2 SmartTec 150x1000x600mm:929828
In: 00 begane grond
Type - PredefinedType: STANDARD; Material: Heraklith® I Tektalan A2 - Steenwol 140 mm, Heraklith® I Tektalan A2 - Houtwollaag - 1000x600mm 10 mm
Type - Pset_ElementShading - Roughness: 304.8 mm
Type - Pset_ManufacturerTypeInformation - Manufacturer: Knauf Insulation B.V.
Type - Pset_ProductRequirements - Category: Walls
Type - Pset_QuantityTakeOff - Reference: Basic Wall:NLRS_41_WA_Heraklith Tektalan A2 SmartTec 150x1000x600mm
Type - Pset_ReinforcementBarPitchOfWall - Description: Tektalan A2 SmartTec - 150mm; Reference: Basic Wall:NLRS_41_WA_Heraklith Tektalan A2 SmartTec 150x1000x600mm
Type - Pset_WallCommon - IsExternal: no; Reference: Basic Wall:NLRS_41_WA_Heraklith Tektalan A2 SmartTec 150x1000x600mm; ThermalTransmittance: 0.236111 kg/K/s3
Type - Pset_Wall Schedule LOD200 - Assembly Code: 41.10; Type Image: Raster image: Heraklith Tektalan A2.jpg; Model: Heraklith® | Tektalan A2 SmartTec is een A2 houtwolcementpaneel gecombineerd met een steenwol-plaat.; Manufacturer: Knauf Insulation B.V.; URL: www.heraklith.nl; Description: Tektalan A2 SmartTec - 150mm; phone: +31(0)162-421245; email: customerservice.nl@knaufinsulation.com; product URL: https://heraklith.nl/houtwol-producten/tektalan-a2-smarttec; warmteweerstand: 4,20 (m2.K/W); NLRS_C_Code_Brandklasse: A2-s1,d0; brandweerstand: REI 120/180 mits verwerkt tegen massief beton conform classificatierapport nr 18203 / 18204; geluidsabsorbtie: 1,00; DoP: W4302GPCPR; NLRS_C_content_creator: Knauf Insulation; NLRS_C_content_versie: V1.0
Classification: 41.10 (Uniformat)
Pset_WallCommon - IsExternal: yes; ExtendToStructure: no; LoadBearing: no
Pset_Wall Schedule LOD200 - Type: Basic Wall: NLRS_41_WA_Heraklith Tektalan A2 SmartTec 150x1000x600mm

# IfcWallStandardCase: Basic Wall:NLRS_41_WA_Heraklith Tektalan A2 SmartTec 175x1000x600mm, Basic Wall:NLRS_41_WA_Heraklith Tektalan A2 SmartTec 175x1000x600mm:929852
In: 00 begane grond
Type - PredefinedType: STANDARD; Material: Heraklith® I Tektalan A2 - Steenwol 165 mm, Heraklith® I Tektalan A2 - Houtwollaag - 1000x600mm 10 mm
Type - Pset_ElementShading - Roughness: 304.8 mm
Type - Pset_ManufacturerTypeInformation - Manufacturer: Knauf Insulation B.V.
Type - Pset_ProductRequirements - Category: Walls
Type - Pset_QuantityTakeOff - Reference: Basic Wall:NLRS_41_WA_Heraklith Tektalan A2 SmartTec 175x1000x600mm
Type - Pset_ReinforcementBarPitchOfWall - Description: Tektalan A2 SmartTec - 175mm; Reference: Basic Wall:NLRS_41_WA_Heraklith Tektalan A2 SmartTec 175x1000x600mm
Type - Pset_WallCommon - IsExternal: no; Reference: Basic Wall:NLRS_41_WA_Heraklith Tektalan A2 SmartTec 175x1000x600mm; ThermalTransmittance: 0.201183 kg/K/s3
Type - Pset_Wall Schedule LOD200 - Assembly Code: 41.10; Type Image: Raster image: Heraklith Tektalan A2.jpg; Model: Heraklith® | Tektalan A2 SmartTec is een A2 houtwolcementpaneel gecombineerd met een steenwol-plaat.; Manufacturer: Knauf Insulation B.V.; URL: www.heraklith.nl; Description: Tektalan A2 SmartTec - 175mm; phone: +31(0)162-421245; email: customerservice.nl@knaufinsulation.com; product URL: https://heraklith.nl/houtwol-producten/tektalan-a2-smarttec; warmteweerstand: 4,95 (m2.K/W); NLRS_C_Code_Brandklasse: A2-s1,d0; brandweerstand: REI 120/180 mits verwerkt tegen massief beton conform classificatierapport nr 18203 / 18204; geluidsabsorbtie: 1,00; DoP: W4302GPCPR; NLRS_C_content_creator: Knauf Insulation; NLRS_C_content_versie: V1.0
Classification: 41.10 (Uniformat)
Pset_WallCommon - IsExternal: yes; ExtendToStructure: no; LoadBearing: no
Pset_Wall Schedule LOD200 - Type: Basic Wall: NLRS_41_WA_Heraklith Tektalan A2 SmartTec 175x1000x600mm

# IfcWallStandardCase: Basic Wall:NLRS_41_WA_Heraklith Tektalan A2 SmartTec 200x1000x600mm, Basic Wall:NLRS_41_WA_Heraklith Tektalan A2 SmartTec 200x1000x600mm:929877
In: 00 begane grond
Type - PredefinedType: STANDARD; Material: Heraklith® I Tektalan A2 - Steenwol 190 mm, Heraklith® I Tektalan A2 - Houtwollaag - 1000x600mm 10 mm
Type - Pset_ElementShading - Roughness: 304.8 mm
Type - Pset_ManufacturerTypeInformation - Manufacturer: Knauf Insulation B.V.
Type - Pset_ProductRequirements - Category: Walls
Type - Pset_QuantityTakeOff - Reference: Basic Wall:NLRS_41_WA_Heraklith Tektalan A2 SmartTec 200x1000x600mm
Type - Pset_ReinforcementBarPitchOfWall - Description: Tektalan A2 SmartTec - 200mm; Reference: Basic Wall:NLRS_41_WA_Heraklith Tektalan A2 SmartTec 200x1000x600mm
Type - Pset_WallCommon - IsExternal: no; Reference: Basic Wall:NLRS_41_WA_Heraklith Tektalan A2 SmartTec 200x1000x600mm; ThermalTransmittance: 0.175258 kg/K/s3
Type - Pset_Wall Schedule LOD200 - Assembly Code: 41.10; Type Image: Raster image: Heraklith Tektalan A2.jpg; Model: Heraklith® | Tektalan A2 SmartTec is een A2 houtwolcementpaneel gecombineerd met een steenwol-plaat.; Manufacturer: Knauf Insulation B.V.; URL: www.heraklith.nl; Description: Tektalan A2 SmartTec - 200mm; phone: +31(0)162-421245; email: customerservice.nl@knaufinsulation.com; product URL: https://heraklith.nl/houtwol-producten/tektalan-a2-smarttec; warmteweerstand: 5,70 (m2.K/W); NLRS_C_Code_Brandklasse: A2-s1,d0; brandweerstand: REI 120/180 mits verwerkt tegen massief beton conform classificatierapport nr 18203 / 18204; geluidsabsorbtie: 0,95; DoP: W4302GPCPR; NLRS_C_content_creator: Knauf Insulation; NLRS_C_content_versie: V1.0
Classification: 41.10 (Uniformat)
Pset_WallCommon - IsExternal: yes; ExtendToStructure: no; LoadBearing: no
Pset_Wall Schedule LOD200 - Type: Basic Wall: NLRS_41_WA_Heraklith Tektalan A2 SmartTec 200x1000x600mm

# IfcWallStandardCase: Basic Wall:NLRS_41_WA_Heraklith Tektalan A2 SmartTec 225x1000x600mm, Basic Wall:NLRS_41_WA_Heraklith Tektalan A2 SmartTec 225x1000x600mm:929902
In: 00 begane grond
Type - PredefinedType: STANDARD; Material: Heraklith® I Tektalan A2 - Steenwol 215 mm, Heraklith® I Tektalan A2 - Houtwollaag - 1000x600mm 10 mm
Type - Pset_ElementShading - Roughness: 304.8 mm
Type - Pset_ManufacturerTypeInformation - Manufacturer: Knauf Insulation B.V.
Type - Pset_ProductRequirements - Category: Walls
Type - Pset_QuantityTakeOff - Reference: Basic Wall:NLRS_41_WA_Heraklith Tektalan A2 SmartTec 225x1000x600mm
Type - Pset_ReinforcementBarPitchOfWall - Description: Tektalan A2 SmartTec - 225mm; Reference: Basic Wall:NLRS_41_WA_Heraklith Tektalan A2 SmartTec 225x1000x600mm
Type - Pset_WallCommon - IsExternal: no; Reference: Basic Wall:NLRS_41_WA_Heraklith Tektalan A2 SmartTec 225x1000x600mm; ThermalTransmittance: 0.155251 kg/K/s3
Type - Pset_Wall Schedule LOD200 - Assembly Code: 41.10; Type Image: Raster image: Heraklith Tektalan A2.jpg; Model: Heraklith® | Tektalan A2 SmartTec is een A2 houtwolcementpaneel gecombineerd met een steenwol-plaat.; Manufacturer: Knauf Insulation B.V.; URL: www.heraklith.nl; Description: Tektalan A2 SmartTec - 225mm; phone: +31(0)162-421245; email: customerservice.nl@knaufinsulation.com; product URL: https://heraklith.nl/houtwol-producten/tektalan-a2-smarttec; warmteweerstand: 6,40 (m2.K/W); NLRS_C_Code_Brandklasse: A2-s1,d0; brandweerstand: REI 120/180 mits verwerkt tegen massief beton conform classificatierapport nr 18203 / 18204; geluidsabsorbtie: 0,95; DoP: W4302GPCPR; NLRS_C_content_creator: Knauf Insulation; NLRS_C_content_versie: V1.0
Classification: 41.10 (Uniformat)
Pset_WallCommon - IsExternal: yes; ExtendToStructure: no; LoadBearing: no
Pset_Wall Schedule LOD200 - Type: Basic Wall: NLRS_41_WA_Heraklith Tektalan A2 SmartTec 225x1000x600mm

# IfcWallStandardCase: Basic Wall:NLRS_41_WA_Heraklith Tektalan A2 SmartTec 50x1000x600mm, Basic Wall:NLRS_41_WA_Heraklith Tektalan A2 SmartTec 50x1000x600mm:905813
In: 00 begane grond
Type - PredefinedType: STANDARD; Material: Heraklith® I Tektalan A2 - Steenwol 40 mm, Heraklith® I Tektalan A2 - Houtwollaag - 1000x600mm 10 mm
Type - Pset_ElementShading - Roughness: 304.8 mm
Type - Pset_ManufacturerTypeInformation - Manufacturer: Knauf Insulation B.V.
Type - Pset_ProductRequirements - Category: Walls
Type - Pset_QuantityTakeOff - Reference: Basic Wall:NLRS_41_WA_Heraklith Tektalan A2 SmartTec 50x1000x600mm
Type - Pset_ReinforcementBarPitchOfWall - Description: Tektalan A2 SmartTec - 50mm; Reference: Basic Wall:NLRS_41_WA_Heraklith Tektalan A2 SmartTec 50x1000x600mm
Type - Pset_WallCommon - Reference: Basic Wall:NLRS_41_WA_Heraklith Tektalan A2 SmartTec 50x1000x600mm; ThermalTransmittance: 0.772727 kg/K/s3; IsExternal: no
Type - Pset_Wall Schedule LOD200 - Assembly Code: 41.10; Type Image: Raster image: Heraklith Tektalan A2.jpg; Model: Heraklith® | Tektalan A2 SmartTec is een A2 houtwolcementpaneel gecombineerd met een steenwol-plaat.; Manufacturer: Knauf Insulation B.V.; URL: www.heraklith.nl; Description: Tektalan A2 SmartTec - 50mm; phone: +31(0)162-421245; email: customerservice.nl@knaufinsulation.com; product URL: https://heraklith.nl/houtwol-producten/tektalan-a2-smarttec; warmteweerstand: 1,25 (m2.K/W); NLRS_C_Code_Brandklasse: A2-s1,d0; brandweerstand: REI 120/180 mits verwerkt tegen massief beton conform classificatierapport nr 18203 / 18204; geluidsabsorbtie: 0,95; DoP: W4302GPCPR; NLRS_C_content_creator: Knauf Insulation; NLRS_C_content_versie: V1.0
Classification: 41.10 (Uniformat)
Pset_WallCommon - IsExternal: yes; ExtendToStructure: no; LoadBearing: no
Pset_Wall Schedule LOD200 - Type: Basic Wall: NLRS_41_WA_Heraklith Tektalan A2 SmartTec 50x1000x600mm

# IfcWallStandardCase: Basic Wall:NLRS_41_WA_Heraklith Tektalan A2 SmartTec 75x1000x600mm, Basic Wall:NLRS_41_WA_Heraklith Tektalan A2 SmartTec 75x1000x600mm:929507
In: 00 begane grond
Type - PredefinedType: STANDARD; Material: Heraklith® I Tektalan A2 - Steenwol 65 mm, Heraklith® I Tektalan A2 - Houtwollaag - 1000x600mm 10 mm
Type - Pset_ElementShading - Roughness: 304.8 mm
Type - Pset_ManufacturerTypeInformation - Manufacturer: Knauf Insulation B.V.
Type - Pset_ProductRequirements - Category: Walls
Type - Pset_QuantityTakeOff - Reference: Basic Wall:NLRS_41_WA_Heraklith Tektalan A2 SmartTec 75x1000x600mm
Type - Pset_ReinforcementBarPitchOfWall - Description: Tektalan A2 SmartTec - 75mm; Reference: Basic Wall:NLRS_41_WA_Heraklith Tektalan A2 SmartTec 75x1000x600mm
Type - Pset_WallCommon - IsExternal: no; Reference: Basic Wall:NLRS_41_WA_Heraklith Tektalan A2 SmartTec 75x1000x600mm; ThermalTransmittance: 0.492754 kg/K/s3
Type - Pset_Wall Schedule LOD200 - Assembly Code: 41.10; Type Image: Raster image: Heraklith Tektalan A2.jpg; Model: Heraklith® | Tektalan A2 SmartTec is een A2 houtwolcementpaneel gecombineerd met een steenwol-plaat.; Manufacturer: Knauf Insulation B.V.; URL: www.heraklith.nl; Description: Tektalan A2 SmartTec - 75mm; phone: +31(0)162-421245; email: customerservice.nl@knaufinsulation.com; product URL: https://heraklith.nl/houtwol-producten/tektalan-a2-smarttec; warmteweerstand: 2,00 (m2.K/W); NLRS_C_Code_Brandklasse: A2-s1,d0; brandweerstand: REI 120/180 mits verwerkt tegen massief beton conform classificatierapport nr 18203 / 18204; geluidsabsorbtie: 0,95; DoP: W4302GPCPR; NLRS_C_content_creator: Knauf Insulation; NLRS_C_content_versie: V1.0
Classification: 41.10 (Uniformat)
Pset_WallCommon - IsExternal: yes; ExtendToStructure: no; LoadBearing: no
Pset_Wall Schedule LOD200 - Type: Basic Wall: NLRS_41_WA_Heraklith Tektalan A2 SmartTec 75x1000x600mm

# IfcWallStandardCase: Basic Wall:NLRS_42_WA_Heraklith Tektalan A2 SmartTec 100x1000x600mm, Basic Wall:NLRS_42_WA_Heraklith Tektalan A2 SmartTec 100x1000x600mm:929629
In: 00 begane grond
Type - PredefinedType: STANDARD; Material: Heraklith® I Tektalan A2 - Steenwol 90 mm, Heraklith® I Tektalan A2 - Houtwollaag - 1000x600mm 10 mm
Type - Pset_ElementShading - Roughness: 304.8 mm
Type - Pset_ManufacturerTypeInformation - Manufacturer: Knauf Insulation B.V.
Type - Pset_ProductRequirements - Category: Walls
Type - Pset_QuantityTakeOff - Reference: Basic Wall:NLRS_42_WA_Heraklith Tektalan A2 SmartTec 100x1000x600mm
Type - Pset_ReinforcementBarPitchOfWall - Description: Tektalan A2 SmartTec - 100mm; Reference: Basic Wall:NLRS_42_WA_Heraklith Tektalan A2 SmartTec 100x1000x600mm
Type - Pset_WallCommon - IsExternal: no; Reference: Basic Wall:NLRS_42_WA_Heraklith Tektalan A2 SmartTec 100x1000x600mm; ThermalTransmittance: 0.361702 kg/K/s3
Type - Pset_Wall Schedule LOD200 - Assembly Code: 42.10; Type Image: Raster image: Heraklith Tektalan A2.jpg; Model: Heraklith® | Tektalan A2 SmartTec is een A2 houtwolcementpaneel gecombineerd met een steenwol-plaat.; Manufacturer: Knauf Insulation B.V.; URL: www.heraklith.nl; Description: Tektalan A2 SmartTec - 100mm; phone: +31(0)162-421245; email: customerservice.nl@knaufinsulation.com; product URL: https://heraklith.nl/houtwol-producten/tektalan-a2-smarttec; warmteweerstand: 2,75 (m2.K/W); NLRS_C_Code_Brandklasse: A2-s1,d0; brandweerstand: REI 120/180 mits verwerkt tegen massief beton conform classificatierapport nr 18203 / 18204; geluidsabsorbtie: 1,00; DoP: W4302GPCPR; NLRS_C_content_creator: Knauf Insulation; NLRS_C_content_versie: V1.0
Classification: 42.10 (Uniformat)
Pset_WallCommon - ExtendToStructure: no; LoadBearing: no
Pset_Wall Schedule LOD200 - Type: Basic Wall: NLRS_42_WA_Heraklith Tektalan A2 SmartTec 100x1000x600mm

# IfcWallStandardCase: Basic Wall:NLRS_42_WA_Heraklith Tektalan A2 SmartTec 125x1000x600mm, Basic Wall:NLRS_42_WA_Heraklith Tektalan A2 SmartTec 125x1000x600mm:929729
In: 00 begane grond
Type - PredefinedType: STANDARD; Material: Heraklith® I Tektalan A2 - Steenwol 115 mm, Heraklith® I Tektalan A2 - Houtwollaag - 1000x600mm 10 mm
Type - Pset_ElementShading - Roughness: 304.8 mm
Type - Pset_ManufacturerTypeInformation - Manufacturer: Knauf Insulation B.V.
Type - Pset_ProductRequirements - Category: Walls
Type - Pset_QuantityTakeOff - Reference: Basic Wall:NLRS_42_WA_Heraklith Tektalan A2 SmartTec 125x1000x600mm
Type - Pset_ReinforcementBarPitchOfWall - Description: Tektalan A2 SmartTec - 125mm; Reference: Basic Wall:NLRS_42_WA_Heraklith Tektalan A2 SmartTec 125x1000x600mm
Type - Pset_WallCommon - IsExternal: no; Reference: Basic Wall:NLRS_42_WA_Heraklith Tektalan A2 SmartTec 125x1000x600mm; ThermalTransmittance: 0.285714 kg/K/s3
Type - Pset_Wall Schedule LOD200 - Assembly Code: 42.10; Type Image: Raster image: Heraklith Tektalan A2.jpg; Model: Heraklith® | Tektalan A2 SmartTec is een A2 houtwolcementpaneel gecombineerd met een steenwol-plaat.; Manufacturer: Knauf Insulation B.V.; URL: www.heraklith.nl; Description: Tektalan A2 SmartTec - 125mm; phone: +31(0)162-421245; email: customerservice.nl@knaufinsulation.com; product URL: https://heraklith.nl/houtwol-producten/tektalan-a2-smarttec; warmteweerstand: 3,50 (m2.K/W); NLRS_C_Code_Brandklasse: A2-s1,d0; brandweerstand: REI 120/180 mits verwerkt tegen massief beton conform classificatierapport nr 18203 / 18204; geluidsabsorbtie: 1,00; DoP: W4302GPCPR; NLRS_C_content_creator: Knauf Insulation; NLRS_C_content_versie: V1.0
Classification: 42.10 (Uniformat)
Pset_WallCommon - ExtendToStructure: no; LoadBearing: no
Pset_Wall Schedule LOD200 - Type: Basic Wall: NLRS_42_WA_Heraklith Tektalan A2 SmartTec 125x1000x600mm

# IfcWallStandardCase: Basic Wall:NLRS_42_WA_Heraklith Tektalan A2 SmartTec 150x1000x600mm, Basic Wall:NLRS_42_WA_Heraklith Tektalan A2 SmartTec 150x1000x600mm:929837
In: 00 begane grond
Type - PredefinedType: STANDARD; Material: Heraklith® I Tektalan A2 - Steenwol 140 mm, Heraklith® I Tektalan A2 - Houtwollaag - 1000x600mm 10 mm
Type - Pset_ElementShading - Roughness: 304.8 mm
Type - Pset_ManufacturerTypeInformation - Manufacturer: Knauf Insulation B.V.
Type - Pset_ProductRequirements - Category: Walls
Type - Pset_QuantityTakeOff - Reference: Basic Wall:NLRS_42_WA_Heraklith Tektalan A2 SmartTec 150x1000x600mm
Type - Pset_ReinforcementBarPitchOfWall - Description: Tektalan A2 SmartTec - 150mm; Reference: Basic Wall:NLRS_42_WA_Heraklith Tektalan A2 SmartTec 150x1000x600mm
Type - Pset_WallCommon - IsExternal: no; Reference: Basic Wall:NLRS_42_WA_Heraklith Tektalan A2 SmartTec 150x1000x600mm; ThermalTransmittance: 0.236111 kg/K/s3
Type - Pset_Wall Schedule LOD200 - Assembly Code: 42.10; Type Image: Raster image: Heraklith Tektalan A2.jpg; Model: Heraklith® | Tektalan A2 SmartTec is een A2 houtwolcementpaneel gecombineerd met een steenwol-plaat.; Manufacturer: Knauf Insulation B.V.; URL: www.heraklith.nl; Description: Tektalan A2 SmartTec - 150mm; phone: +31(0)162-421245; email: customerservice.nl@knaufinsulation.com; product URL: https://heraklith.nl/houtwol-producten/tektalan-a2-smarttec; warmteweerstand: 4,20 (m2.K/W); NLRS_C_Code_Brandklasse: A2-s1,d0; brandweerstand: REI 120/180 mits verwerkt tegen massief beton conform classificatierapport nr 18203 / 18204; geluidsabsorbtie: 1,00; DoP: W4302GPCPR; NLRS_C_content_creator: Knauf Insulation; NLRS_C_content_versie: V1.0
Classification: 42.10 (Uniformat)
Pset_WallCommon - ExtendToStructure: no; LoadBearing: no
Pset_Wall Schedule LOD200 - Type: Basic Wall: NLRS_42_WA_Heraklith Tektalan A2 SmartTec 150x1000x600mm

# IfcWallStandardCase: Basic Wall:NLRS_42_WA_Heraklith Tektalan A2 SmartTec 175x1000x600mm, Basic Wall:NLRS_42_WA_Heraklith Tektalan A2 SmartTec 175x1000x600mm:929861
In: 00 begane grond
Type - PredefinedType: STANDARD; Material: Heraklith® I Tektalan A2 - Steenwol 165 mm, Heraklith® I Tektalan A2 - Houtwollaag - 1000x600mm 10 mm
Type - Pset_ElementShading - Roughness: 304.8 mm
Type - Pset_ManufacturerTypeInformation - Manufacturer: Knauf Insulation B.V.
Type - Pset_ProductRequirements - Category: Walls
Type - Pset_QuantityTakeOff - Reference: Basic Wall:NLRS_42_WA_Heraklith Tektalan A2 SmartTec 175x1000x600mm
Type - Pset_ReinforcementBarPitchOfWall - Description: Tektalan A2 SmartTec - 175mm; Reference: Basic Wall:NLRS_42_WA_Heraklith Tektalan A2 SmartTec 175x1000x600mm
Type - Pset_WallCommon - IsExternal: no; Reference: Basic Wall:NLRS_42_WA_Heraklith Tektalan A2 SmartTec 175x1000x600mm; ThermalTransmittance: 0.201183 kg/K/s3
Type - Pset_Wall Schedule LOD200 - Assembly Code: 42.10; Type Image: Raster image: Heraklith Tektalan A2.jpg; Model: Heraklith® | Tektalan A2 SmartTec is een A2 houtwolcementpaneel gecombineerd met een steenwol-plaat.; Manufacturer: Knauf Insulation B.V.; URL: www.heraklith.nl; Description: Tektalan A2 SmartTec - 175mm; phone: +31(0)162-421245; email: customerservice.nl@knaufinsulation.com; product URL: https://heraklith.nl/houtwol-producten/tektalan-a2-smarttec; warmteweerstand: 4,95 (m2.K/W); NLRS_C_Code_Brandklasse: A2-s1,d0; brandweerstand: REI 120/180 mits verwerkt tegen massief beton conform classificatierapport nr 18203 / 18204; geluidsabsorbtie: 1,00; DoP: W4302GPCPR; NLRS_C_content_creator: Knauf Insulation; NLRS_C_content_versie: V1.0
Classification: 42.10 (Uniformat)
Pset_WallCommon - ExtendToStructure: no; LoadBearing: no
Pset_Wall Schedule LOD200 - Type: Basic Wall: NLRS_42_WA_Heraklith Tektalan A2 SmartTec 175x1000x600mm

# IfcWallStandardCase: Basic Wall:NLRS_42_WA_Heraklith Tektalan A2 SmartTec 200x1000x600mm, Basic Wall:NLRS_42_WA_Heraklith Tektalan A2 SmartTec 200x1000x600mm:929886
In: 00 begane grond
Type - PredefinedType: STANDARD; Material: Heraklith® I Tektalan A2 - Steenwol 190 mm, Heraklith® I Tektalan A2 - Houtwollaag - 1000x600mm 10 mm
Type - Pset_ElementShading - Roughness: 304.8 mm
Type - Pset_ManufacturerTypeInformation - Manufacturer: Knauf Insulation B.V.
Type - Pset_ProductRequirements - Category: Walls
Type - Pset_QuantityTakeOff - Reference: Basic Wall:NLRS_42_WA_Heraklith Tektalan A2 SmartTec 200x1000x600mm
Type - Pset_ReinforcementBarPitchOfWall - Description: Tektalan A2 SmartTec - 200mm; Reference: Basic Wall:NLRS_42_WA_Heraklith Tektalan A2 SmartTec 200x1000x600mm
Type - Pset_WallCommon - IsExternal: no; Reference: Basic Wall:NLRS_42_WA_Heraklith Tektalan A2 SmartTec 200x1000x600mm; ThermalTransmittance: 0.175258 kg/K/s3
Type - Pset_Wall Schedule LOD200 - Assembly Code: 42.10; Type Image: Raster image: Heraklith Tektalan A2.jpg; Model: Heraklith® | Tektalan A2 SmartTec is een A2 houtwolcementpaneel gecombineerd met een steenwol-plaat.; Manufacturer: Knauf Insulation B.V.; URL: www.heraklith.nl; Description: Tektalan A2 SmartTec - 200mm; phone: +31(0)162-421245; email: customerservice.nl@knaufinsulation.com; product URL: https://heraklith.nl/houtwol-producten/tektalan-a2-smarttec; warmteweerstand: 5,70 (m2.K/W); NLRS_C_Code_Brandklasse: A2-s1,d0; brandweerstand: REI 120/180 mits verwerkt tegen massief beton conform classificatierapport nr 18203 / 18204; geluidsabsorbtie: 0,95; DoP: W4302GPCPR; NLRS_C_content_creator: Knauf Insulation; NLRS_C_content_versie: V1.0
Classification: 42.10 (Uniformat)
Pset_WallCommon - ExtendToStructure: no; LoadBearing: no
Pset_Wall Schedule LOD200 - Type: Basic Wall: NLRS_42_WA_Heraklith Tektalan A2 SmartTec 200x1000x600mm

# IfcWallStandardCase: Basic Wall:NLRS_42_WA_Heraklith Tektalan A2 SmartTec 225x1000x600mm, Basic Wall:NLRS_42_WA_Heraklith Tektalan A2 SmartTec 225x1000x600mm:929911
In: 00 begane grond
Type - PredefinedType: STANDARD; Material: Heraklith® I Tektalan A2 - Steenwol 215 mm, Heraklith® I Tektalan A2 - Houtwollaag - 1000x600mm 10 mm
Type - Pset_ElementShading - Roughness: 304.8 mm
Type - Pset_ManufacturerTypeInformation - Manufacturer: Knauf Insulation B.V.
Type - Pset_ProductRequirements - Category: Walls
Type - Pset_QuantityTakeOff - Reference: Basic Wall:NLRS_42_WA_Heraklith Tektalan A2 SmartTec 225x1000x600mm
Type - Pset_ReinforcementBarPitchOfWall - Description: Tektalan A2 SmartTec - 225mm; Reference: Basic Wall:NLRS_42_WA_Heraklith Tektalan A2 SmartTec 225x1000x600mm
Type - Pset_WallCommon - IsExternal: no; Reference: Basic Wall:NLRS_42_WA_Heraklith Tektalan A2 SmartTec 225x1000x600mm; ThermalTransmittance: 0.155251 kg/K/s3
Type - Pset_Wall Schedule LOD200 - Assembly Code: 42.10; Type Image: Raster image: Heraklith Tektalan A2.jpg; Model: Heraklith® | Tektalan A2 SmartTec is een A2 houtwolcementpaneel gecombineerd met een steenwol-plaat.; Manufacturer: Knauf Insulation B.V.; URL: www.heraklith.nl; Description: Tektalan A2 SmartTec - 225mm; phone: +31(0)162-421245; email: customerservice.nl@knaufinsulation.com; product URL: https://heraklith.nl/houtwol-producten/tektalan-a2-smarttec; warmteweerstand: 6,40 (m2.K/W); NLRS_C_Code_Brandklasse: A2-s1,d0; brandweerstand: REI 120/180 mits verwerkt tegen massief beton conform classificatierapport nr 18203 / 18204; geluidsabsorbtie: 0,95; DoP: W4302GPCPR; NLRS_C_content_creator: Knauf Insulation; NLRS_C_content_versie: V1.0
Classification: 42.10 (Uniformat)
Pset_WallCommon - ExtendToStructure: no; LoadBearing: no
Pset_Wall Schedule LOD200 - Type: Basic Wall: NLRS_42_WA_Heraklith Tektalan A2 SmartTec 225x1000x600mm

# IfcWallStandardCase: Basic Wall:NLRS_42_WA_Heraklith Tektalan A2 SmartTec 50x1000x600mm, Basic Wall:NLRS_42_WA_Heraklith Tektalan A2 SmartTec 50x1000x600mm:905886
In: 00 begane grond
Type - PredefinedType: STANDARD; Material: Heraklith® I Tektalan A2 - Steenwol 40 mm, Heraklith® I Tektalan A2 - Houtwollaag - 1000x600mm 15 mm
Type - Pset_ElementShading - Roughness: 304.8 mm
Type - Pset_ManufacturerTypeInformation - Manufacturer: Knauf Insulation B.V.
Type - Pset_ProductRequirements - Category: Walls
Type - Pset_QuantityTakeOff - Reference: Basic Wall:NLRS_42_WA_Heraklith Tektalan A2 SmartTec 50x1000x600mm
Type - Pset_ReinforcementBarPitchOfWall - Description: Tektalan A2 SmartTec - 50mm; Reference: Basic Wall:NLRS_42_WA_Heraklith Tektalan A2 SmartTec 50x1000x600mm
Type - Pset_WallCommon - IsExternal: no; Reference: Basic Wall:NLRS_42_WA_Heraklith Tektalan A2 SmartTec 50x1000x600mm; ThermalTransmittance: 0.73913 kg/K/s3
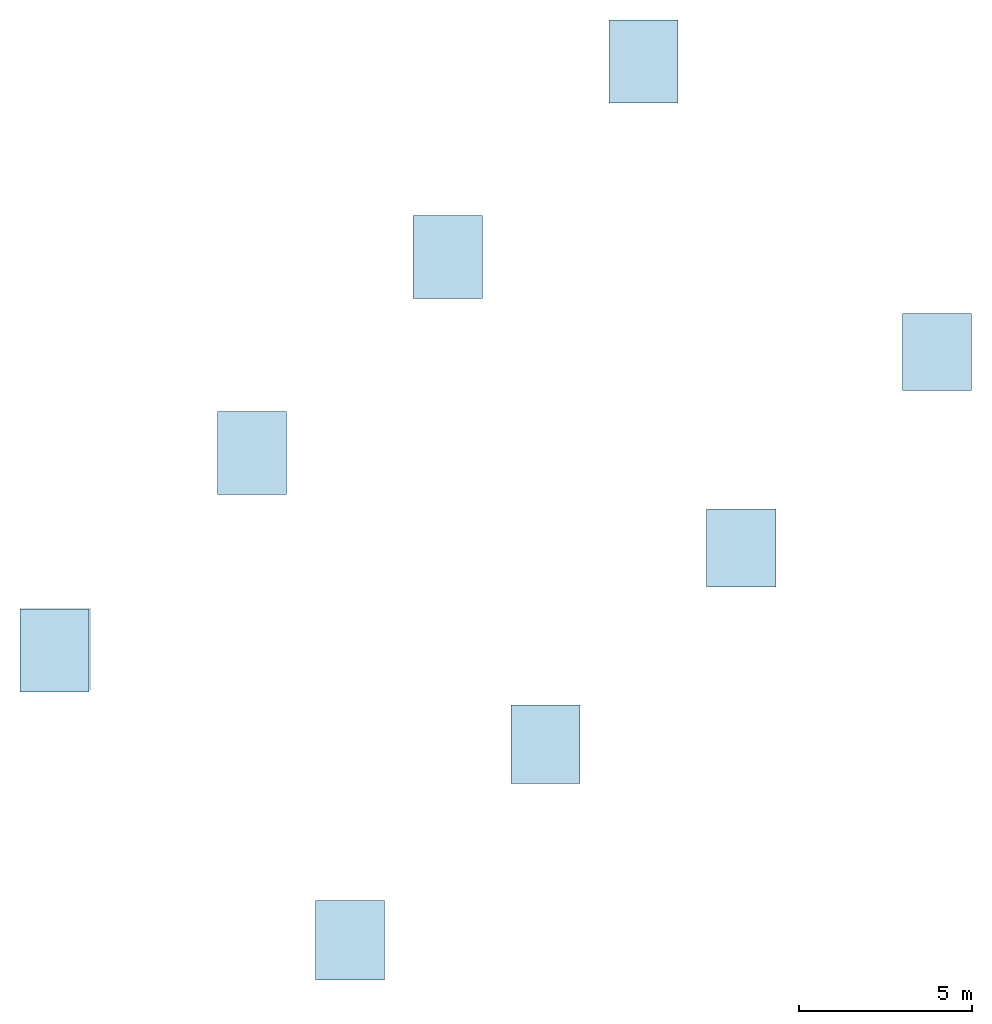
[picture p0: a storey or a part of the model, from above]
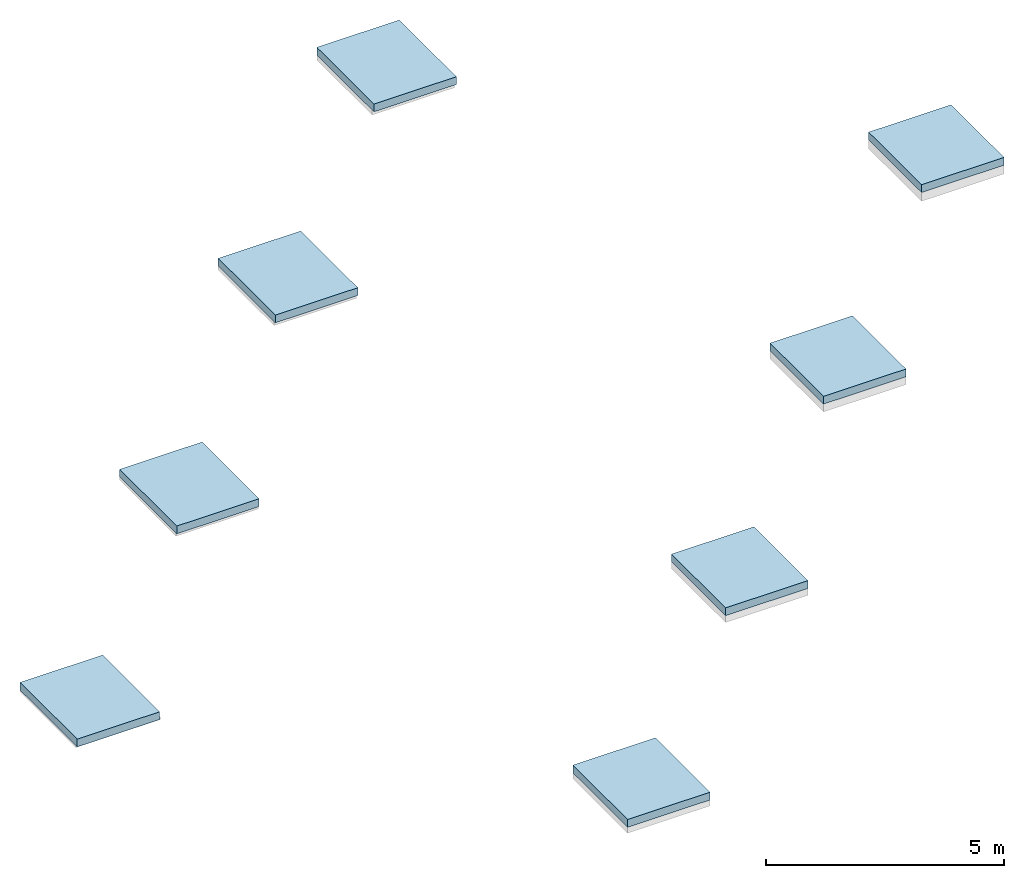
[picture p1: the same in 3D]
Properties of the parts of a building model (IFC2X3), part 2 of 2

# IfcWallStandardCase: Basic Wall:NLRS_42_WA_Heraklith Tektalan A2 SmartTec 50x1000x600mm, Basic Wall:NLRS_42_WA_Heraklith Tektalan A2 SmartTec 50x1000x600mm:905886
Type - Pset_Wall Schedule LOD200 - Assembly Code: 42.10; Type Image: Raster image: Heraklith Tektalan A2.jpg; Model: Heraklith® | Tektalan A2 SmartTec is een A2 houtwolcementpaneel gecombineerd met een steenwol-plaat.; Manufacturer: Knauf Insulation B.V.; URL: www.heraklith.nl; Description: Tektalan A2 SmartTec - 50mm; phone: +31(0)162-421245; email: customerservice.nl@knaufinsulation.com; product URL: https://heraklith.nl/houtwol-producten/tektalan-a2-smarttec; warmteweerstand: 1,25 (m2.K/W); NLRS_C_Code_Brandklasse: A2-s1,d0; brandweerstand: REI 120/180 mits verwerkt tegen massief beton conform classificatierapport nr 18203 / 18204; geluidsabsorbtie: 0,95; DoP: W4302GPCPR; NLRS_C_content_creator: Knauf Insulation; NLRS_C_content_versie: V1.0
Classification: 42.10 (Uniformat)
Pset_WallCommon - ExtendToStructure: no; LoadBearing: no
Pset_Wall Schedule LOD200 - Type: Basic Wall: NLRS_42_WA_Heraklith Tektalan A2 SmartTec 50x1000x600mm

# IfcWallStandardCase: Basic Wall:NLRS_42_WA_Heraklith Tektalan A2 SmartTec 75x1000x600mm, Basic Wall:NLRS_42_WA_Heraklith Tektalan A2 SmartTec 75x1000x600mm:929516
In: 00 begane grond
Type - PredefinedType: STANDARD; Material: Heraklith® I Tektalan A2 - Steenwol 65 mm, Heraklith® I Tektalan A2 - Houtwollaag - 1000x600mm 15 mm
Type - Pset_ElementShading - Roughness: 304.8 mm
Type - Pset_ManufacturerTypeInformation - Manufacturer: Knauf Insulation B.V.
Type - Pset_ProductRequirements - Category: Walls
Type - Pset_QuantityTakeOff - Reference: Basic Wall:NLRS_42_WA_Heraklith Tektalan A2 SmartTec 75x1000x600mm
Type - Pset_ReinforcementBarPitchOfWall - Description: Tektalan A2 SmartTec - 75mm; Reference: Basic Wall:NLRS_42_WA_Heraklith Tektalan A2 SmartTec 75x1000x600mm
Type - Pset_WallCommon - IsExternal: no; Reference: Basic Wall:NLRS_42_WA_Heraklith Tektalan A2 SmartTec 75x1000x600mm; ThermalTransmittance: 0.478873 kg/K/s3
Type - Pset_Wall Schedule LOD200 - Assembly Code: 42.10; Type Image: Raster image: Heraklith Tektalan A2.jpg; Model: Heraklith® | Tektalan A2 SmartTec is een A2 houtwolcementpaneel gecombineerd met een steenwol-plaat.; Manufacturer: Knauf Insulation B.V.; URL: www.heraklith.nl; Description: Tektalan A2 SmartTec - 75mm; phone: +31(0)162-421245; email: customerservice.nl@knaufinsulation.com; product URL: https://heraklith.nl/houtwol-producten/tektalan-a2-smarttec; warmteweerstand: 2,00 (m2.K/W); NLRS_C_Code_Brandklasse: A2-s1,d0; brandweerstand: REI 120/180 mits verwerkt tegen massief beton conform classificatierapport nr 18203 / 18204; geluidsabsorbtie: 0,95; DoP: W4302GPCPR; NLRS_C_content_creator: Knauf Insulation; NLRS_C_content_versie: V1.0
Classification: 42.10 (Uniformat)
Pset_WallCommon - ExtendToStructure: no; LoadBearing: no
Pset_Wall Schedule LOD200 - Type: Basic Wall: NLRS_42_WA_Heraklith Tektalan A2 SmartTec 75x1000x600mm
